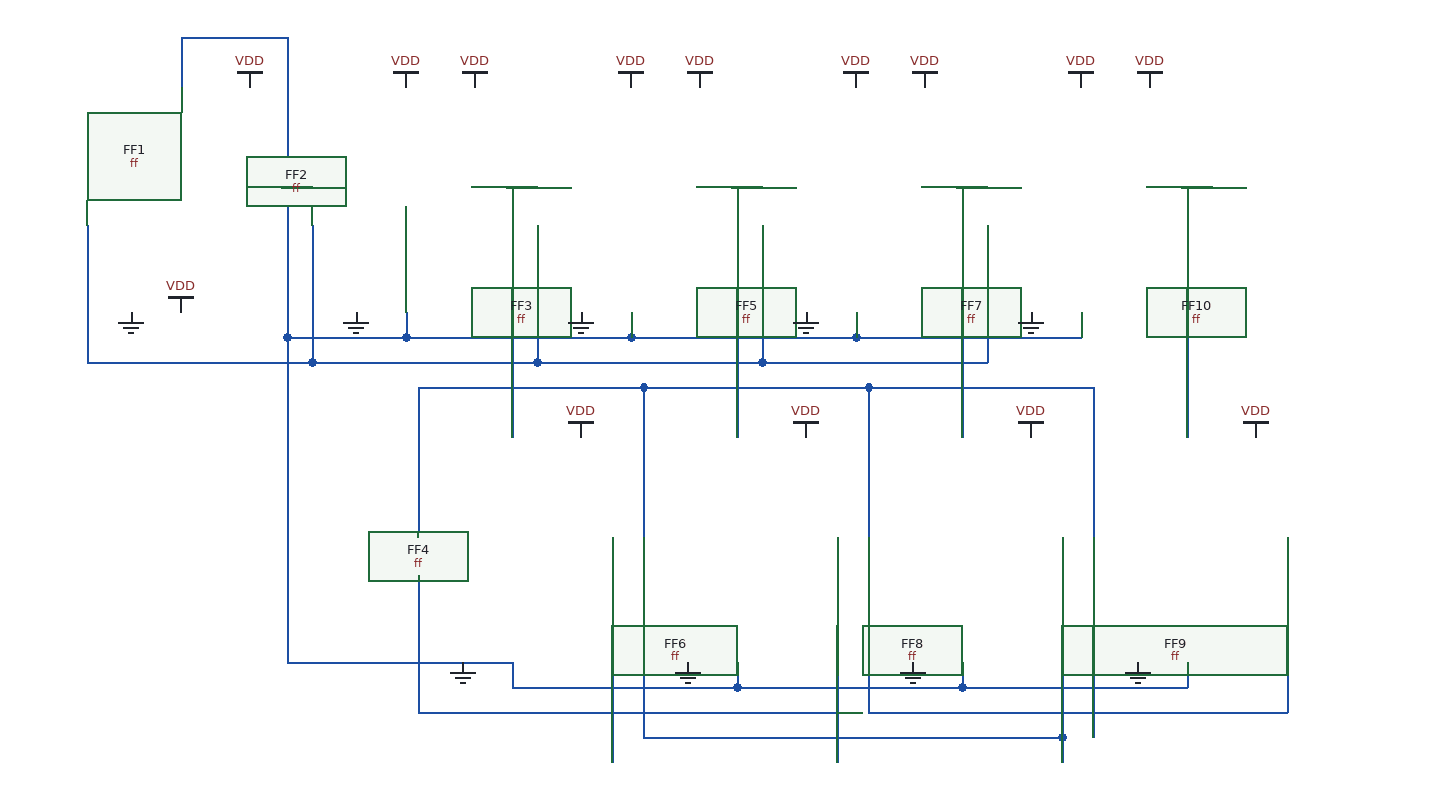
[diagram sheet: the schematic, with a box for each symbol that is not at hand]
v {xschem version=3.4.0 file_version=1.2
}
G {}
K {}
V {}
S {}
E {}
N 155 -120 180 -120 {
lab=#net1}
N 335 -120 360 -120 {
lab=#net2}
N 180 20 360 20 {
lab=#net3}
N 0 20 180 20 {
lab=#net3}
N 360 20 540 20 {
lab=#net3}
N 255 -20 255 0 {
lab=GND}
N 435 -20 435 0 {
lab=GND}
N 0 -90 -0 20 {
lab=#net3}
N 180 -90 180 20 {
lab=#net3}
N 360 -90 360 20 {
lab=#net3}
N 255 0 435 -0 {
lab=GND}
N 615 -20 615 0 {
lab=GND}
N 435 0 615 0 {
lab=GND}
N 540 -90 540 20 {
lab=#net3}
N 515 -120 540 -120 {
lab=#net4}
N 265 40 445 40 {
lab=#net5}
N 160 0 255 0 {
lab=GND}
N 75 -240 75 -200 {
lab=GND}
N 75 -240 160 -240 {
lab=GND}
N 160 -240 160 0 {
lab=GND}
N 340 260 340 280 {
lab=GND}
N 160 0 160 260 {
lab=GND}
N 160 260 340 260 {
lab=GND}
N 265 190 265 300 {
lab=#net6}
N 265 300 600 300 {
lab=#net6}
N 695 -120 720 -120 {
lab=#net7}
N 340 280 520 280 {
lab=GND}
N 520 260 520 280 {
lab=GND}
N 520 280 700 280 {
lab=GND}
N 700 260 700 280 {
lab=GND}
N 880 260 880 280 {
lab=GND}
N 700 280 880 280 {
lab=GND}
N 265 40 265 160 {
lab=#net5}
N 340 -120 340 80 {
lab=#net2}
N 445 40 445 160 {
lab=#net5}
N 520 -120 520 80 {
lab=#net4}
N 700 -120 700 80 {
lab=#net7}
N 720 -90 720 20 {
lab=#net3}
N 540 20 720 20 {
lab=#net3}
N 615 0 795 0 {
lab=GND}
N 795 -20 795 -0 {
lab=GND}
N 445 190 445 320 {
lab=#net8}
N 600 160 600 340 {
lab=#net6}
N 420 160 420 340 {
lab=#net9}
N 625 40 625 160 {
lab=#net10}
N 805 40 805 160 {
lab=#net11}
N 445 320 780 320 {
lab=#net8}
N 780 160 780 320 {
lab=#net8}
N 625 190 625 300 {
lab=#net12}
N 625 300 960 300 {
lab=#net12}
N 960 160 960 300 {
lab=#net12}
N 805 190 805 320 {
lab=#net13}
N 780 320 780 340 {
lab=#net8}
N 875 -120 900 -120 {}
N 880 -120 880 80 {}
N 445 40 625 40 {}
N 625 40 805 40 {}
C {ff.sym} 20 -40 0 0 {name=FF1
model=gf180mcu_fd_sc_mcu7t5v0__dffrsnq_1
}
C {ff.sym} 200 -40 0 0 {name=FF2
model=gf180mcu_fd_sc_mcu7t5v0__dffrsnq_1
}
C {ff.sym} 380 -40 0 0 {name=FF3
model=gf180mcu_fd_sc_mcu7t5v0__dffrsnq_1
}
C {devices/vdd.sym} 255 -200 0 0 {name=l1 lab=VDD}
C {devices/vdd.sym} 435 -200 0 0 {name=l2 lab=VDD}
C {ff.sym} 285 240 0 0 {name=FF4
model=gf180mcu_fd_sc_mcu7t5v0__dffrsnq_1
}
C {devices/vdd.sym} 75 -20 2 0 {name=l5 lab=VDD}
C {ff.sym} 560 -40 0 0 {name=FF5
model=gf180mcu_fd_sc_mcu7t5v0__dffrsnq_1
}
C {devices/gnd.sym} 35 -20 0 0 {name=l7 lab=GND}
C {devices/gnd.sym} 215 -20 0 0 {name=l3 lab=GND}
C {devices/gnd.sym} 395 -20 0 0 {name=l4 lab=GND}
C {ff.sym} 465 240 0 0 {name=FF6
model=gf180mcu_fd_sc_mcu7t5v0__dffrsnq_1
}
C {devices/vdd.sym} 130 -200 0 0 {name=l6 lab=VDD}
C {devices/gnd.sym} 300 260 0 0 {name=l8 lab=GND}
C {devices/gnd.sym} 575 -20 0 0 {name=l9 lab=GND}
C {ff.sym} 740 -40 0 0 {name=FF7
model=gf180mcu_fd_sc_mcu7t5v0__dffrsnq_1
}
C {ff.sym} 645 240 0 0 {name=FF8
model=gf180mcu_fd_sc_mcu7t5v0__dffrsnq_1
}
C {ff.sym} 825 240 0 0 {name=FF9
model=gf180mcu_fd_sc_mcu7t5v0__dffrsnq_1
}
C {devices/gnd.sym} 480 260 0 0 {name=l10 lab=GND}
C {devices/gnd.sym} 660 260 0 0 {name=l11 lab=GND}
C {devices/gnd.sym} 840 260 0 0 {name=l12 lab=GND}
C {devices/vdd.sym} 615 -200 0 0 {name=l13 lab=VDD}
C {devices/vdd.sym} 795 -200 0 0 {name=l14 lab=VDD}
C {devices/vdd.sym} 310 -200 0 0 {name=l15 lab=VDD}
C {devices/vdd.sym} 490 -200 0 0 {name=l16 lab=VDD}
C {devices/vdd.sym} 670 -200 0 0 {name=l17 lab=VDD}
C {devices/vdd.sym} 850 -200 0 0 {name=l18 lab=VDD}
C {devices/vdd.sym} 395 80 0 0 {name=l19 lab=VDD}
C {devices/vdd.sym} 575 80 0 0 {name=l20 lab=VDD}
C {devices/vdd.sym} 755 80 0 0 {name=l21 lab=VDD}
C {devices/vdd.sym} 935 80 0 0 {name=l22 lab=VDD}
C {devices/gnd.sym} 755 -20 0 0 {name=l23 lab=GND}
C {ff.sym} 920 -40 0 0 {name=FF10
model=gf180mcu_fd_sc_mcu7t5v0__dffrsnq_1
}
